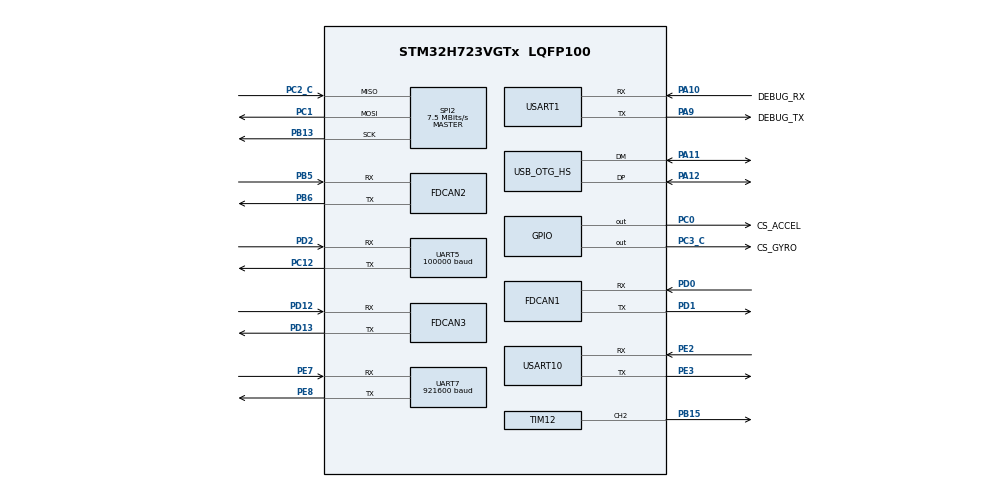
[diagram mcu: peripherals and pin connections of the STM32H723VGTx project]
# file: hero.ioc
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CORTEX_M7.MPU_Control=__NULL
CORTEX_M7.default_mode_Activation=0
Dma.Request0=UART5_RX
Dma.Request1=UART7_RX
Dma.Request2=USART10_RX
Dma.Request3=USART10_TX
Dma.UART5_RX.0.Direction=DMA_PERIPH_TO_MEMORY
Dma.UART5_RX.0.EventEnable=DISABLE
Dma.UART5_RX.0.FIFOMode=DMA_FIFOMODE_DISABLE
Dma.UART5_RX.0.Instance=DMA1_Stream0
Dma.UART5_RX.0.MemDataAlignment=DMA_MDATAALIGN_BYTE
Dma.UART5_RX.0.MemInc=DMA_MINC_ENABLE
Dma.UART5_RX.0.Mode=DMA_CIRCULAR
Dma.UART5_RX.0.PeriphDataAlignment=DMA_PDATAALIGN_BYTE
Dma.UART5_RX.0.PeriphInc=DMA_PINC_DISABLE
Dma.UART5_RX.0.Polarity=HAL_DMAMUX_REQ_GEN_RISING
Dma.UART5_RX.0.Priority=DMA_PRIORITY_VERY_HIGH
Dma.UART5_RX.0.RequestNumber=1
Dma.UART5_RX.0.SignalID=NONE
Dma.UART5_RX.0.SyncEnable=DISABLE
Dma.UART5_RX.0.SyncPolarity=HAL_DMAMUX_SYNC_NO_EVENT
Dma.UART5_RX.0.SyncRequestNumber=1
Dma.UART5_RX.0.SyncSignalID=NONE
Dma.UART7_RX.1.Direction=DMA_PERIPH_TO_MEMORY
Dma.UART7_RX.1.EventEnable=DISABLE
Dma.UART7_RX.1.FIFOMode=DMA_FIFOMODE_DISABLE
Dma.UART7_RX.1.Instance=DMA1_Stream1
Dma.UART7_RX.1.MemDataAlignment=DMA_MDATAALIGN_BYTE
Dma.UART7_RX.1.MemInc=DMA_MINC_ENABLE
Dma.UART7_RX.1.Mode=DMA_CIRCULAR
Dma.UART7_RX.1.PeriphDataAlignment=DMA_PDATAALIGN_BYTE
Dma.UART7_RX.1.PeriphInc=DMA_PINC_DISABLE
Dma.UART7_RX.1.Polarity=HAL_DMAMUX_REQ_GEN_RISING
Dma.UART7_RX.1.Priority=DMA_PRIORITY_VERY_HIGH
Dma.UART7_RX.1.RequestNumber=1
Dma.UART7_RX.1.SignalID=NONE
Dma.UART7_RX.1.SyncEnable=DISABLE
Dma.UART7_RX.1.SyncPolarity=HAL_DMAMUX_SYNC_NO_EVENT
Dma.UART7_RX.1.SyncRequestNumber=1
Dma.UART7_RX.1.SyncSignalID=NONE
Dma.USART10_RX.2.Direction=DMA_PERIPH_TO_MEMORY
Dma.USART10_RX.2.EventEnable=DISABLE
Dma.USART10_RX.2.FIFOMode=DMA_FIFOMODE_DISABLE
Dma.USART10_RX.2.Instance=DMA1_Stream2
Dma.USART10_RX.2.MemDataAlignment=DMA_MDATAALIGN_BYTE
Dma.USART10_RX.2.MemInc=DMA_MINC_ENABLE
Dma.USART10_RX.2.Mode=DMA_CIRCULAR
Dma.USART10_RX.2.PeriphDataAlignment=DMA_PDATAALIGN_BYTE
Dma.USART10_RX.2.PeriphInc=DMA_PINC_DISABLE
Dma.USART10_RX.2.Polarity=HAL_DMAMUX_REQ_GEN_RISING
Dma.USART10_RX.2.Priority=DMA_PRIORITY_MEDIUM
Dma.USART10_RX.2.RequestNumber=1
Dma.USART10_RX.2.SignalID=NONE
Dma.USART10_RX.2.SyncEnable=DISABLE
Dma.USART10_RX.2.SyncPolarity=HAL_DMAMUX_SYNC_NO_EVENT
Dma.USART10_RX.2.SyncRequestNumber=1
Dma.USART10_RX.2.SyncSignalID=NONE
Dma.USART10_TX.3.Direction=DMA_MEMORY_TO_PERIPH
Dma.USART10_TX.3.EventEnable=DISABLE
Dma.USART10_TX.3.FIFOMode=DMA_FIFOMODE_DISABLE
Dma.USART10_TX.3.Instance=DMA1_Stream3
Dma.USART10_TX.3.MemDataAlignment=DMA_MDATAALIGN_BYTE
Dma.USART10_TX.3.MemInc=DMA_MINC_ENABLE
Dma.USART10_TX.3.Mode=DMA_NORMAL
Dma.USART10_TX.3.PeriphDataAlignment=DMA_PDATAALIGN_BYTE
Dma.USART10_TX.3.PeriphInc=DMA_PINC_DISABLE
Dma.USART10_TX.3.Polarity=HAL_DMAMUX_REQ_GEN_RISING
Dma.USART10_TX.3.Priority=DMA_PRIORITY_MEDIUM
Dma.USART10_TX.3.RequestNumber=1
Dma.USART10_TX.3.SignalID=NONE
Dma.USART10_TX.3.SyncEnable=DISABLE
Dma.USART10_TX.3.SyncPolarity=HAL_DMAMUX_SYNC_NO_EVENT
Dma.USART10_TX.3.SyncRequestNumber=1
Dma.USART10_TX.3.SyncSignalID=NONE
FDCAN1.AutoRetransmission=ENABLE
FDCAN1.CalculateBaudRateNominal=1000000
FDCAN1.CalculateTimeBitNominal=1000
FDCAN1.CalculateTimeQuantumNominal=25.0
FDCAN1.DataPrescaler=3
FDCAN1.DataSyncJumpWidth=10
FDCAN1.DataTimeSeg1=29
FDCAN1.DataTimeSeg2=10
FDCAN1.ExtFiltersNbr=8
FDCAN1.NominalPrescaler=3
FDCAN1.NominalSyncJumpWidth=10
FDCAN1.NominalTimeSeg1=29
FDCAN1.NominalTimeSeg2=10
FDCAN1.ProtocolException=ENABLE
FDCAN1.RxFifo0ElmtsNbr=32
FDCAN1.StdFiltersNbr=16
FDCAN1.TxBuffersNbr=0
FDCAN1.TxFifoQueueElmtsNbr=32
FDCAN2.AutoRetransmission=ENABLE
FDCAN2.CalculateBaudRateNominal=1000000
FDCAN2.CalculateTimeBitNominal=1000
FDCAN2.CalculateTimeQuantumNominal=25.0
FDCAN2.DataPrescaler=3
FDCAN2.DataSyncJumpWidth=10
FDCAN2.DataTimeSeg1=29
FDCAN2.DataTimeSeg2=10
FDCAN2.ExtFiltersNbr=8
FDCAN2.MessageRAMOffset=853
FDCAN2.NominalPrescaler=3
FDCAN2.NominalSyncJumpWidth=10
FDCAN2.NominalTimeSeg1=29
FDCAN2.NominalTimeSeg2=10
FDCAN2.ProtocolException=ENABLE
FDCAN2.RxFifo0ElmtsNbr=32
FDCAN2.StdFiltersNbr=16
FDCAN2.TxFifoQueueElmtsNbr=32
FDCAN3.AutoRetransmission=ENABLE
FDCAN3.CalculateBaudRateNominal=1000000
FDCAN3.CalculateTimeBitNominal=1000
FDCAN3.CalculateTimeQuantumNominal=25.0
FDCAN3.DataPrescaler=3
FDCAN3.DataSyncJumpWidth=10
FDCAN3.DataTimeSeg1=29
FDCAN3.DataTimeSeg2=10
FDCAN3.ExtFiltersNbr=8
FDCAN3.MessageRAMOffset=1706
FDCAN3.NominalPrescaler=3
FDCAN3.NominalSyncJumpWidth=10
FDCAN3.NominalTimeSeg1=29
FDCAN3.NominalTimeSeg2=10
FDCAN3.ProtocolException=ENABLE
FDCAN3.RxFifo0ElmtsNbr=32
FDCAN3.RxFifo1ElmtsNbr=0
FDCAN3.StdFiltersNbr=16
FDCAN3.TxFifoQueueElmtsNbr=32
IWDG1.Reload=4095
Mcu.Family=STM32H7
Mcu.Name=STM32H723VGTx
Mcu.Package=LQFP100
NVIC.DMA1_Stream0_IRQn=true\:0\:0\:false\:false\:true\:false\:true\:true
NVIC.DMA1_Stream1_IRQn=true\:0\:0\:false\:false\:true\:false\:true\:true
NVIC.DMA1_Stream2_IRQn=true\:0\:0\:false\:false\:true\:false\:true\:true
NVIC.DMA1_Stream3_IRQn=true\:0\:0\:false\:false\:true\:false\:true\:true
NVIC.FDCAN1_IT0_IRQn=true\:0\:0\:false\:false\:true\:true\:true\:true
NVIC.FDCAN2_IT0_IRQn=true\:0\:0\:false\:false\:true\:true\:true\:true
NVIC.FDCAN3_IT0_IRQn=true\:0\:0\:false\:false\:true\:true\:true\:true
NVIC.OTG_HS_IRQn=true\:0\:0\:false\:false\:true\:true\:true\:true
NVIC.PriorityGroup=NVIC_PRIORITYGROUP_4
NVIC.TIM15_IRQn=true\:1\:0\:true\:false\:true\:true\:true\:true
NVIC.TIM2_IRQn=true\:2\:0\:true\:false\:true\:true\:true\:true
NVIC.TIM4_IRQn=true\:1\:0\:true\:false\:true\:true\:true\:true
NVIC.TIM5_IRQn=true\:1\:0\:true\:false\:true\:true\:true\:true
NVIC.TIM8_BRK_TIM12_IRQn=true\:1\:0\:true\:false\:true\:true\:true\:true
NVIC.UART5_IRQn=true\:0\:0\:true\:false\:true\:true\:true\:true
NVIC.UART7_IRQn=true\:0\:0\:false\:false\:true\:true\:true\:true
NVIC.USART10_IRQn=true\:0\:0\:false\:false\:true\:true\:true\:true
PA10.GPIO_Label=DEBUG_RX
PA10.Mode=Asynchronous
PA10.Signal=USART1_RX
PA11.Mode=Device_Only_FS
PA11.Signal=USB_OTG_HS_DM
PA12.Mode=Device_Only_FS
PA12.Signal=USB_OTG_HS_DP
PA13(JTMS/SWDIO).Mode=Serial_Wire
PA13(JTMS/SWDIO).Signal=DEBUG_JTMS-SWDIO
PA14(JTCK/SWCLK).Mode=Serial_Wire
PA14(JTCK/SWCLK).Signal=DEBUG_JTCK-SWCLK
PA9.GPIO_Label=DEBUG_TX
PA9.Mode=Asynchronous
PA9.Signal=USART1_TX
PB13.GPIO_Speed=GPIO_SPEED_FREQ_VERY_HIGH
PB13.Mode=Full_Duplex_Master
PB13.Signal=SPI2_SCK
PB15.Signal=S_TIM12_CH2
PB5.Mode=FDCAN_Activate
PB5.Signal=FDCAN2_RX
PB6.Mode=FDCAN_Activate
PB6.Signal=FDCAN2_TX
PC0.GPIO_Label=CS_ACCEL
PC0.GPIO_Speed=GPIO_SPEED_FREQ_VERY_HIGH
PC0.PinState=GPIO_PIN_SET
PC0.Signal=GPIO_Output
PC1.GPIO_Speed=GPIO_SPEED_FREQ_VERY_HIGH
PC1.Mode=Full_Duplex_Master
PC1.Signal=SPI2_MOSI
PC12.Mode=Asynchronous
PC12.Signal=UART5_TX
PC2_C.GPIO_Speed=GPIO_SPEED_FREQ_VERY_HIGH
PC2_C.Mode=Full_Duplex_Master
PC2_C.Signal=SPI2_MISO
PC3_C.GPIO_Label=CS_GYRO
PC3_C.GPIO_Speed=GPIO_SPEED_FREQ_VERY_HIGH
PC3_C.PinState=GPIO_PIN_SET
PC3_C.Signal=GPIO_Output
PD0.Mode=FDCAN_Activate
PD0.Signal=FDCAN1_RX
PD1.Mode=FDCAN_Activate
PD1.Signal=FDCAN1_TX
PD12.Mode=FDCAN_Activate
PD12.Signal=FDCAN3_RX
PD13.Mode=FDCAN_Activate
PD13.Signal=FDCAN3_TX
PD2.Mode=Asynchronous
PD2.Signal=UART5_RX
PE2.Mode=Asynchronous
PE2.Signal=USART10_RX
PE3.Mode=Asynchronous
PE3.Signal=USART10_TX
PE7.Mode=Asynchronous
PE7.Signal=UART7_RX
PE8.Mode=Asynchronous
PE8.Signal=UART7_TX
PH0-OSC_IN.Mode=HSE-External-Oscillator
PH0-OSC_IN.Signal=RCC_OSC_IN
PH1-OSC_OUT.Mode=HSE-External-Oscillator
PH1-OSC_OUT.Signal=RCC_OSC_OUT
ProjectManager.HeapSize=0x200
ProjectManager.StackSize=0x400
ProjectManager.TargetToolchain=CMake
RCC.ADCFreq_Value=120000000
RCC.APB1Freq_Value=137500000
RCC.APB2Freq_Value=137500000
RCC.APB3Freq_Value=137500000
RCC.APB4Freq_Value=137500000
RCC.CortexFreq_Value=550000000
RCC.D1PPRE=RCC_APB3_DIV2
RCC.D2PPRE1=RCC_APB1_DIV2
RCC.D2PPRE2=RCC_APB2_DIV2
RCC.D3PPRE=RCC_APB4_DIV2
RCC.DIVM1=12
RCC.DIVM2=2
RCC.DIVM3=12
RCC.DIVN1=275
RCC.DIVN2=20
RCC.DIVN3=96
RCC.DIVP1=1
RCC.DIVP3=4
RCC.DIVQ1=4
RCC.DIVQ3=4
RCC.FDCANCLockSelection=RCC_FDCANCLKSOURCE_PLL2
RCC.HCLKFreq_Value=275000000
RCC.HPRE=RCC_HCLK_DIV2
RCC.HSE_VALUE=24000000
RCC.PLL2FRACN=0
RCC.PLLFRACN=0
RCC.PLLSourceVirtual=RCC_PLLSOURCE_HSE
RCC.SPI123CLockSelection=RCC_SPI123CLKSOURCE_PLL2
RCC.SYSCLKFreq_VALUE=550000000
RCC.SYSCLKSource=RCC_SYSCLKSOURCE_PLLCLK
RCC.USBCLockSelection=RCC_USBCLKSOURCE_PLL3
RCC.USBFreq_Value=48000000
SH.S_TIM12_CH2.0=TIM12_CH2,PWM Generation2 CH2
SPI2.BaudRatePrescaler=SPI_BAUDRATEPRESCALER_16
SPI2.CLKPhase=SPI_PHASE_2EDGE
SPI2.CLKPolarity=SPI_POLARITY_HIGH
SPI2.CalculateBaudRate=7.5 MBits/s
SPI2.DataSize=SPI_DATASIZE_8BIT
SPI2.Direction=SPI_DIRECTION_2LINES
SPI2.Mode=SPI_MODE_MASTER
SPI2.VirtualType=VM_MASTER
STMicroelectronics.X-CUBE-ALGOBUILD.1.4.0.LibraryCcDSPOoLibraryJjDSPOoLibrary=true
TIM12.Channel-PWM\ Generation2\ CH2=TIM_CHANNEL_2
TIM12.Period=8000-1
TIM12.Prescaler=240-1
TIM15.Period=8000-1
TIM15.Prescaler=240-1
TIM2.Period=5000-1
TIM2.Prescaler=240-1
TIM4.Period=1000-1
TIM4.Prescaler=240-1
TIM5.Period=1000-1
TIM5.Prescaler=240-1
UART5.BaudRate=100000
UART5.Mode=MODE_RX
UART5.Parity=PARITY_EVEN
UART5.WordLength=WORDLENGTH_9B
UART7.BaudRate=921600
USART1.VirtualMode-Asynchronous=VM_ASYNC
USART10.FIFOMode=FIFOMODE_ENABLE
USART10.VirtualMode=VM_ASYNC
USB_DEVICE.CLASS_NAME_HS=CDC
USB_DEVICE.VirtualMode=Cdc
USB_DEVICE.VirtualModeHS=Cdc_HS
USB_OTG_HS.VirtualMode-Device_Only_FS=Device_Only_FS
VP_IWDG1_VS_IWDG.Mode=IWDG_Activate
VP_MEMORYMAP_VS_MEMORYMAP.Mode=CurAppReg
VP_STMicroelectronics.X-CUBE-ALGOBUILD_VS_DSPOoLibraryJjLibrary_1.4.0_1.4.0.Mode=DSPOoLibraryJjLibrary
VP_TIM12_VS_ClockSourceINT.Mode=Internal
VP_TIM15_VS_ClockSourceINT.Mode=Internal
VP_TIM2_VS_ClockSourceINT.Mode=Internal
VP_TIM4_VS_ClockSourceINT.Mode=Internal
VP_TIM5_VS_ClockSourceINT.Mode=Internal
VP_USB_DEVICE_VS_USB_DEVICE_CDC_HS.Mode=CDC_HS
board=custom

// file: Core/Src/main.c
/* USER CODE BEGIN Header */
/**
 ******************************************************************************
 * @file           : main.c
 * @brief          : Main program body
 ******************************************************************************
 * @attention
 *
 * Copyright (c) 2026 STMicroelectronics.
 * All rights reserved.
 *
 * This software is licensed under terms that can be found in the LICENSE file
 * in the root directory of this software component.
 * If no LICENSE file comes with this software, it is provided AS-IS.
 *
 ******************************************************************************
 */
/* USER CODE END Header */
#include "main.h"
#include "dma.h"
#include "fdcan.h"
#include "gpio.h"
#include "iwdg.h"
#include "spi.h"
#include "tim.h"
#include "usart.h"
#include "usb_device.h"

/* USER CODE BEGIN Includes */
#include "bsp_dwt.h"
#include "bsp_fdcan.h"
#include "bsp_tim.h"
#include "bsp_usart.h"

#include "buzzer.h"
#include "dbus.h"
#include "dji_motor.h"
#include "dm_motor.h"
#include "imu.h"
#include "mi_motor.h"

#include "log.h"
#include "vofa.h"

/* USER CODE END Includes */

/* USER CODE BEGIN PD */
#ifndef PI
#define PI (3.14159265358979f)
#endif
/* USER CODE END PD */

/* USER CODE BEGIN PV */
int system_ready = 0;
int control_ready = 0;
int tx_status = 114514;
float ref_vel = 0;
float measure_pos;
float ref_pos;
uint64_t count = 0;
float trq = 0;
float kp = 10;
float kd = 0.5;
float vel = 0;
uint8_t cmd[8] = {0x00, 0x02, 0x00, 0x00, 0x00, 0x00, 0x00, 0x00};
/* USER CODE END PV */

void SystemClock_Config(void);

int main(void)
{

	/* MCU Configuration--------------------------------------------------------*/

	/* Reset of all peripherals, Initializes the Flash interface and the Systick. */
	HAL_Init();

	/* Configure the system clock */
	SystemClock_Config();

	/* Initialize all configured peripherals */
	MX_GPIO_Init();
	MX_DMA_Init();
	MX_UART5_Init();
	MX_FDCAN1_Init();
	MX_FDCAN3_Init();
	MX_SPI2_Init();
	MX_TIM2_Init();
	MX_USART1_UART_Init();
	MX_TIM5_Init();
	MX_TIM4_Init();
	MX_TIM12_Init();
	MX_TIM15_Init();
	MX_FDCAN2_Init();
	MX_UART7_Init();
	MX_IWDG1_Init();
	MX_USART10_UART_Init();
	MX_USB_DEVICE_Init();
	/* USER CODE BEGIN 2 */
	dwt_init(480);
	usart_init();
	can_init();
	tim_init();
	imu_init();
	vofa_init();
	mi_motor_enable();
	dm4310_enable();
	/* system ready signal and buzzer */
	system_ready = 1;
	buzzer_beep_ms(200);

	LOG_DEBUG("========================================");	 /* for yellow color */
	LOG_ERROR("FUCKING ROBOMASTER STM32 RTT Terminal Test"); /* for red color */
	LOG_DEBUG("========================================");	 /* for yellow color */
	/* USER CODE END 2 */

	/* Infinite loop */
	/* USER CODE BEGIN WHILE */
	while (1) {
		dwt_delay_ms(10);
		count++;
		vofa_send(1.0f, 2.0f);
		HAL_IWDG_Refresh(&hiwdg1);
		// tx_status = can_transmit(&hfdcan1, 0x3FE, CAN_ID_STD, cmd);
		// ref_vel = dbus_data.ls_x * 5;
		// dm6006_set_vel(ref_vel);
		// measure_pos = dm6006_get_pos(dm6006.raw_pos);
		// measure_pos = dm6006_set_pos(0.0);
		// tx_status = can_transmit(&hfdcan1, 0x3FE, CAN_ID_STD, cmd);
		/*armor_task();*/
		/* USER CODE END WHILE */

	}
}

void SystemClock_Config(void)
{
	RCC_OscInitTypeDef RCC_OscInitStruct = {0};
	RCC_ClkInitTypeDef RCC_ClkInitStruct = {0};

	/** Supply configuration update enable
	 */
	HAL_PWREx_ConfigSupply(PWR_LDO_SUPPLY);

	/** Configure the main internal regulator output voltage
	 */
	__HAL_PWR_VOLTAGESCALING_CONFIG(PWR_REGULATOR_VOLTAGE_SCALE0);

	while (!__HAL_PWR_GET_FLAG(PWR_FLAG_VOSRDY)) {
	}

	/** Initializes the RCC Oscillators according to the specified parameters
	 * in the RCC_OscInitTypeDef structure.
	 */
	RCC_OscInitStruct.OscillatorType =
	    RCC_OSCILLATORTYPE_HSI48 | RCC_OSCILLATORTYPE_LSI | RCC_OSCILLATORTYPE_HSE;
	RCC_OscInitStruct.HSEState = RCC_HSE_ON;
	RCC_OscInitStruct.LSIState = RCC_LSI_ON;
	RCC_OscInitStruct.HSI48State = RCC_HSI48_ON;
	RCC_OscInitStruct.PLL.PLLState = RCC_PLL_ON;
	RCC_OscInitStruct.PLL.PLLSource = RCC_PLLSOURCE_HSE;
	RCC_OscInitStruct.PLL.PLLM = 2;
	RCC_OscInitStruct.PLL.PLLN = 40;
	RCC_OscInitStruct.PLL.PLLP = 1;
	RCC_OscInitStruct.PLL.PLLQ = 4;
	RCC_OscInitStruct.PLL.PLLR = 2;
	RCC_OscInitStruct.PLL.PLLRGE = RCC_PLL1VCIRANGE_3;
	RCC_OscInitStruct.PLL.PLLVCOSEL = RCC_PLL1VCOWIDE;
	RCC_OscInitStruct.PLL.PLLFRACN = 0;
	if (HAL_RCC_OscConfig(&RCC_OscInitStruct) != HAL_OK) {
		Error_Handler();
	}

	/** Initializes the CPU, AHB and APB buses clocks
	 */
	RCC_ClkInitStruct.ClockType = RCC_CLOCKTYPE_HCLK | RCC_CLOCKTYPE_SYSCLK |
				      RCC_CLOCKTYPE_PCLK1 | RCC_CLOCKTYPE_PCLK2 |
				      RCC_CLOCKTYPE_D3PCLK1 | RCC_CLOCKTYPE_D1PCLK1;
	RCC_ClkInitStruct.SYSCLKSource = RCC_SYSCLKSOURCE_PLLCLK;
	RCC_ClkInitStruct.SYSCLKDivider = RCC_SYSCLK_DIV1;
	RCC_ClkInitStruct.AHBCLKDivider = RCC_HCLK_DIV2;
	RCC_ClkInitStruct.APB3CLKDivider = RCC_APB3_DIV2;
	RCC_ClkInitStruct.APB1CLKDivider = RCC_APB1_DIV2;
	RCC_ClkInitStruct.APB2CLKDivider = RCC_APB2_DIV2;
	RCC_ClkInitStruct.APB4CLKDivider = RCC_APB4_DIV2;

	if (HAL_RCC_ClockConfig(&RCC_ClkInitStruct, FLASH_LATENCY_3) != HAL_OK) {
		Error_Handler();
	}
}

void Error_Handler(void)
{
	/* USER CODE BEGIN Error_Handler_Debug */
	/* User can add his own implementation to report the HAL error return state
	 */
	__disable_irq();
	while (1) {
	}
	/* USER CODE END Error_Handler_Debug */
}
#ifdef USE_FULL_ASSERT
/**
 * @brief  Reports the name of the source file and the source line number
 *         where the assert_param error has occurred.
 * @param  file: pointer to the source file name
 * @param  line: assert_param error line source number
 * @retval None
 */
void assert_failed(uint8_t *file, uint32_t line)
{
	/* USER CODE BEGIN 6 */
	/* User can add his own implementation to report the file name and line
	   number, ex: printf("Wrong parameters value: file %s on line %d\r\n", file,
	   line) */
	/* USER CODE END 6 */
}
#endif /* USE_FULL_ASSERT */
